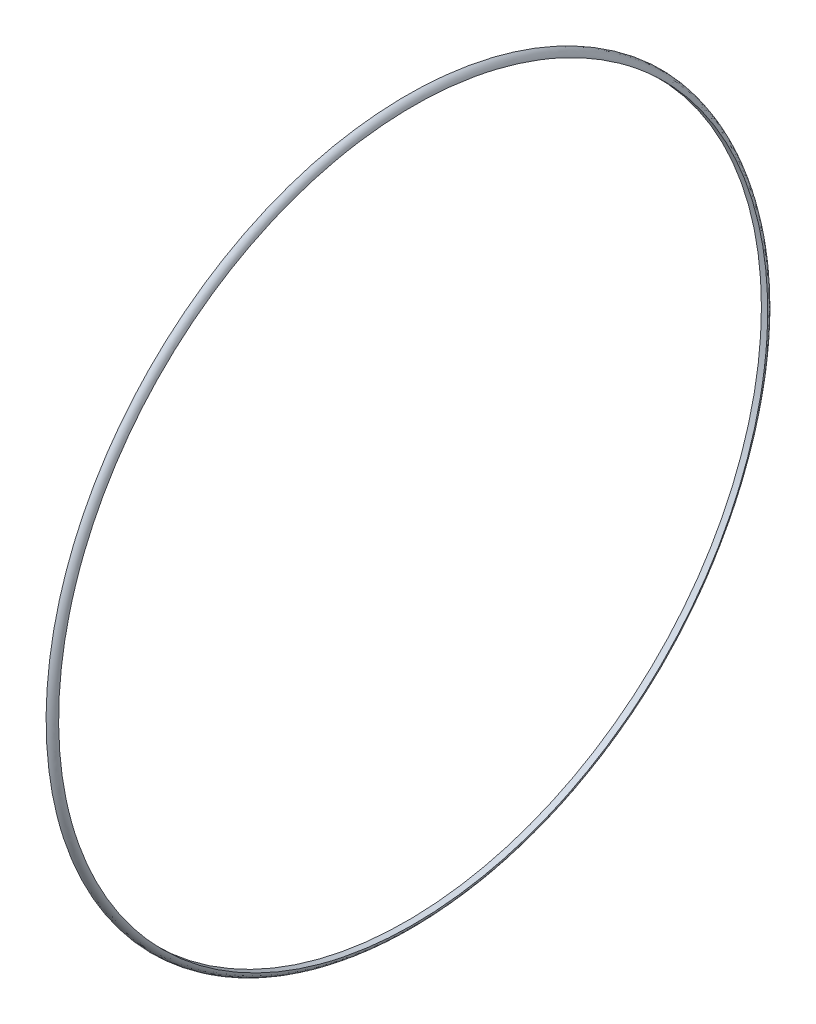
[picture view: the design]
ISO-10303-21;
HEADER;
FILE_DESCRIPTION(('STEP AP214'),'2;1');
FILE_NAME('part.step','',(''),(''),'','','');
FILE_SCHEMA(('AUTOMOTIVE_DESIGN { 1 0 10303 214 1 1 1 1 }'));
ENDSEC;
DATA;
#1=APPLICATION_CONTEXT('core data for automotive mechanical design processes');
#2=APPLICATION_PROTOCOL_DEFINITION('international standard','automotive_design',2000,#1);
#3=PRODUCT_CONTEXT('',#1,'mechanical');
#4=PRODUCT('Part','Part','',(#3));
#5=PRODUCT_RELATED_PRODUCT_CATEGORY('part','',(#4));
#6=PRODUCT_DEFINITION_FORMATION('','',#4);
#7=PRODUCT_DEFINITION_CONTEXT('part definition',#1,'design');
#8=PRODUCT_DEFINITION('design','',#6,#7);
#9=PRODUCT_DEFINITION_SHAPE('','',#8);
#10=(LENGTH_UNIT() NAMED_UNIT(*) SI_UNIT(.MILLI.,.METRE.));
#11=(NAMED_UNIT(*) PLANE_ANGLE_UNIT() SI_UNIT($,.RADIAN.));
#12=(NAMED_UNIT(*) SI_UNIT($,.STERADIAN.) SOLID_ANGLE_UNIT());
#13=UNCERTAINTY_MEASURE_WITH_UNIT(LENGTH_MEASURE(1.E-05),#10,'distance_accuracy_value','');
#14=(GEOMETRIC_REPRESENTATION_CONTEXT(3) GLOBAL_UNCERTAINTY_ASSIGNED_CONTEXT((#13)) GLOBAL_UNIT_ASSIGNED_CONTEXT((#10,
#11,#12)) REPRESENTATION_CONTEXT('',''));
#15=CARTESIAN_POINT('',(0.,0.,0.));
#16=DIRECTION('',(0.,0.,1.));
#17=DIRECTION('',(1.,0.,0.));
#18=AXIS2_PLACEMENT_3D('',#15,#16,#17);
#19=CARTESIAN_POINT('',(860.942596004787,1.34057465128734E-12,574.769949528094));
#20=DIRECTION('',(-1.,0.,0.));
#21=DIRECTION('',(0.,0.,1.));
#22=AXIS2_PLACEMENT_3D('',#19,#20,#21);
#23=CYLINDRICAL_SURFACE('',#22,15.113);
#24=CARTESIAN_POINT('',(857.907296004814,-5.03581855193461E-09,559.656949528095));
#25=CARTESIAN_POINT('',(857.907295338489,-0.199487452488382,559.656946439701));
#26=CARTESIAN_POINT('',(857.907260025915,-0.398936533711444,559.660896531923));
#27=CARTESIAN_POINT('',(857.90706303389,-0.998143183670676,559.684642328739));
#28=CARTESIAN_POINT('',(857.906809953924,-1.39751407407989,559.71638294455));
#29=CARTESIAN_POINT('',(857.906111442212,-2.19292731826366,559.811521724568));
#30=CARTESIAN_POINT('',(857.905665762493,-2.5889647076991,559.874960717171));
#31=CARTESIAN_POINT('',(857.904690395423,-3.37962317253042,560.034091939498));
#32=CARTESIAN_POINT('',(857.904159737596,-3.77416620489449,560.13017322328));
#33=CARTESIAN_POINT('',(857.90321322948,-4.55440358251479,560.353814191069));
#34=CARTESIAN_POINT('',(857.902797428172,-4.9400940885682,560.481387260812));
#35=CARTESIAN_POINT('',(857.902256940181,-5.69995149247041,560.767161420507));
#36=CARTESIAN_POINT('',(857.902132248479,-6.07411858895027,560.925361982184));
#37=CARTESIAN_POINT('',(857.902231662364,-6.80835340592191,561.271293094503));
#38=CARTESIAN_POINT('',(857.902455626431,-7.16842678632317,561.459011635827));
#39=CARTESIAN_POINT('',(857.903167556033,-7.88381970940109,561.869418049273));
#40=CARTESIAN_POINT('',(857.90366391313,-8.23859898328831,562.093048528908));
#41=CARTESIAN_POINT('',(857.904705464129,-8.92798209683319,562.568756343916));
#42=CARTESIAN_POINT('',(857.905250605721,-9.26260691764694,562.820803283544));
#43=CARTESIAN_POINT('',(857.906188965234,-9.9098059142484,563.351818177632));
#44=CARTESIAN_POINT('',(857.906582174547,-10.222378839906,563.630787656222));
#45=CARTESIAN_POINT('',(857.907093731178,-10.8235686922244,564.213969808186));
#46=CARTESIAN_POINT('',(857.90721181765,-11.1121626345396,564.5182061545));
#47=CARTESIAN_POINT('',(857.907296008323,-11.6667378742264,565.153809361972));
#48=CARTESIAN_POINT('',(857.907260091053,-11.9323714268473,565.485480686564));
#49=CARTESIAN_POINT('',(857.907205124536,-12.3091514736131,565.998821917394));
#50=CARTESIAN_POINT('',(857.90718661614,-12.4311591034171,566.172617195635));
#51=CARTESIAN_POINT('',(857.907172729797,-12.6677771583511,566.525237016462));
#52=CARTESIAN_POINT('',(857.907177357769,-12.7823856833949,566.704062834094));
#53=CARTESIAN_POINT('',(857.907218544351,-13.1149696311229,567.247916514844));
#54=CARTESIAN_POINT('',(857.907282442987,-13.3214956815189,567.62003752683));
#55=CARTESIAN_POINT('',(857.907433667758,-13.7024159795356,568.380316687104));
#56=CARTESIAN_POINT('',(857.907520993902,-13.8768102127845,568.768474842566));
#57=CARTESIAN_POINT('',(857.907648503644,-14.1921828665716,569.557918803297));
#58=CARTESIAN_POINT('',(857.907688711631,-14.3331785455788,569.959197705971));
#59=CARTESIAN_POINT('',(857.907686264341,-14.5808600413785,570.772214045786));
#60=CARTESIAN_POINT('',(857.907643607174,-14.6875450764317,571.183951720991));
#61=CARTESIAN_POINT('',(857.907510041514,-14.8658172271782,572.01482341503));
#62=CARTESIAN_POINT('',(857.907419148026,-14.9374152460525,572.433955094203));
#63=CARTESIAN_POINT('',(857.907312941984,-15.0450530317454,573.276757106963));
#64=CARTESIAN_POINT('',(857.907297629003,-15.0810929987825,573.700427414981));
#65=CARTESIAN_POINT('',(857.907284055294,-15.1173616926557,574.549351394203));
#66=CARTESIAN_POINT('',(857.907285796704,-15.1175859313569,574.974605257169));
#67=CARTESIAN_POINT('',(857.907303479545,-15.0822102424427,575.823620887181));
#68=CARTESIAN_POINT('',(857.907319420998,-15.0466102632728,576.247382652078));
#69=CARTESIAN_POINT('',(857.907423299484,-14.9398362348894,577.090424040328));
#70=CARTESIAN_POINT('',(857.907511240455,-14.868660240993,577.509703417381));
#71=CARTESIAN_POINT('',(857.907634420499,-14.6912392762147,578.340775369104));
#72=CARTESIAN_POINT('',(857.907669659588,-14.5849943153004,578.752567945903));
#73=CARTESIAN_POINT('',(857.907665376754,-14.3381937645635,579.565728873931));
#74=CARTESIAN_POINT('',(857.907625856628,-14.1976389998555,579.96709747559));
#75=CARTESIAN_POINT('',(857.90752646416,-13.8832167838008,580.756567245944));
#76=CARTESIAN_POINT('',(857.907466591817,-13.7093493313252,581.144668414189));
#77=CARTESIAN_POINT('',(857.907356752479,-13.3295390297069,581.904841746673));
#78=CARTESIAN_POINT('',(857.907306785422,-13.1235963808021,582.276914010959));
#79=CARTESIAN_POINT('',(857.907208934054,-12.6810990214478,583.002386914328));
#80=CARTESIAN_POINT('',(857.907161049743,-12.4445443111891,583.355787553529));
#81=CARTESIAN_POINT('',(857.907071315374,-11.9425036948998,584.041405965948));
#82=CARTESIAN_POINT('',(857.907029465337,-11.6770176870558,584.373623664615));
#83=CARTESIAN_POINT('',(857.906974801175,-11.119002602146,585.014512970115));
#84=CARTESIAN_POINT('',(857.906961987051,-10.8264735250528,585.323184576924));
#85=CARTESIAN_POINT('',(857.906974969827,-10.2164522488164,585.914786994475));
#86=CARTESIAN_POINT('',(857.907000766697,-9.89896006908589,586.197717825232));
#87=CARTESIAN_POINT('',(857.907073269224,-9.24126956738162,586.735827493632));
#88=CARTESIAN_POINT('',(857.907119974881,-8.90107124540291,586.991006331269));
#89=CARTESIAN_POINT('',(857.907213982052,-8.20038709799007,587.471797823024));
#90=CARTESIAN_POINT('',(857.907261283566,-7.83990127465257,587.697410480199));
#91=CARTESIAN_POINT('',(857.907361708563,-7.10120492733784,588.117465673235));
#92=CARTESIAN_POINT('',(857.907414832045,-6.72299440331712,588.311908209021));
#93=CARTESIAN_POINT('',(857.907528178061,-5.95153722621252,588.668240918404));
#94=CARTESIAN_POINT('',(857.907588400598,-5.55829056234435,588.830131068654));
#95=CARTESIAN_POINT('',(857.907664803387,-4.75955710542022,589.120207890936));
#96=CARTESIAN_POINT('',(857.90768098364,-4.35407031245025,589.248394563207));
#97=CARTESIAN_POINT('',(857.907631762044,-3.53373952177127,589.470153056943));
#98=CARTESIAN_POINT('',(857.907566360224,-3.11889552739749,589.563724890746));
#99=CARTESIAN_POINT('',(857.907428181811,-2.28279947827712,589.71558853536));
#100=CARTESIAN_POINT('',(857.907355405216,-1.86154742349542,589.773880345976));
#101=CARTESIAN_POINT('',(857.907289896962,-1.01563007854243,589.854769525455));
#102=CARTESIAN_POINT('',(857.907297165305,-0.590964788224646,589.877366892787));
#103=CARTESIAN_POINT('',(857.907293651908,0.258759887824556,589.886706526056));
#104=CARTESIAN_POINT('',(857.907282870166,0.683819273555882,589.873448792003));
#105=CARTESIAN_POINT('',(857.90732328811,1.53131043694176,589.811172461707));
#106=CARTESIAN_POINT('',(857.907374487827,1.95374221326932,589.762153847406));
#107=CARTESIAN_POINT('',(857.907507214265,2.79297469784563,589.62870423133));
#108=CARTESIAN_POINT('',(857.907588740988,3.20977540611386,589.544273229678));
#109=CARTESIAN_POINT('',(857.907674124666,4.03478220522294,589.34059917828));
#110=CARTESIAN_POINT('',(857.907677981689,4.44298830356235,589.221356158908));
#111=CARTESIAN_POINT('',(857.907626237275,5.24790414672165,588.94890579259));
#112=CARTESIAN_POINT('',(857.907570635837,5.6446138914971,588.795698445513));
#113=CARTESIAN_POINT('',(857.90745919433,6.42371654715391,588.456408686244));
#114=CARTESIAN_POINT('',(857.907403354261,6.80610946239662,588.270326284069));
#115=CARTESIAN_POINT('',(857.907299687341,7.55386000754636,587.866609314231));
#116=CARTESIAN_POINT('',(857.90725186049,7.91921763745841,587.648974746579));
#117=CARTESIAN_POINT('',(857.90715600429,8.63030055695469,587.183700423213));
#118=CARTESIAN_POINT('',(857.907107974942,8.97602582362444,586.936060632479));
#119=CARTESIAN_POINT('',(857.907026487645,9.64538565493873,586.412536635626));
#120=CARTESIAN_POINT('',(857.906993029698,9.9690202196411,586.136652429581));
#121=CARTESIAN_POINT('',(857.906961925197,10.5918968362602,585.55860186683));
#122=CARTESIAN_POINT('',(857.906964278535,10.8911389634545,585.256435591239));
#123=CARTESIAN_POINT('',(857.907003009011,11.46310439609,584.627968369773));
#124=CARTESIAN_POINT('',(857.90703938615,11.7358277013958,584.301667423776));
#125=CARTESIAN_POINT('',(857.907123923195,12.2528180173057,583.627248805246));
#126=CARTESIAN_POINT('',(857.907172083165,12.4970848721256,583.279131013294));
#127=CARTESIAN_POINT('',(857.907268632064,12.9554239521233,582.563555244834));
#128=CARTESIAN_POINT('',(857.907317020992,13.169496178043,582.196097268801));
#129=CARTESIAN_POINT('',(857.907422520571,13.5659289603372,581.444444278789));
#130=CARTESIAN_POINT('',(857.907479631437,13.7482887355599,581.060248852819));
#131=CARTESIAN_POINT('',(857.90758848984,14.0799936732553,580.277860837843));
#132=CARTESIAN_POINT('',(857.907640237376,14.2293388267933,579.879668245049));
#133=CARTESIAN_POINT('',(857.907678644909,14.4939454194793,579.072139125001));
#134=CARTESIAN_POINT('',(857.907665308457,14.6092087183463,578.662803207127));
#135=CARTESIAN_POINT('',(857.907566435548,14.804843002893,577.8358771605));
#136=CARTESIAN_POINT('',(857.907480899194,14.8852140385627,577.418287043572));
#137=CARTESIAN_POINT('',(857.907355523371,15.0104844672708,576.577875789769));
#138=CARTESIAN_POINT('',(857.907315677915,15.0553885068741,576.155055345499));
#139=CARTESIAN_POINT('',(857.907283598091,15.1094234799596,575.307132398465));
#140=CARTESIAN_POINT('',(857.907291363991,15.1185542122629,574.882029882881));
#141=CARTESIAN_POINT('',(857.907295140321,15.1009742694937,574.032429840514));
#142=CARTESIAN_POINT('',(857.907291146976,15.0742520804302,573.60793255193));
#143=CARTESIAN_POINT('',(857.907367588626,14.9851371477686,572.762708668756));
#144=CARTESIAN_POINT('',(857.9074480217,14.9227452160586,572.341981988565));
#145=CARTESIAN_POINT('',(857.907592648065,14.7626931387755,571.507062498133));
#146=CARTESIAN_POINT('',(857.907656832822,14.6650145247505,571.092873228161));
#147=CARTESIAN_POINT('',(857.907700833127,14.435078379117,570.274164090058));
#148=CARTESIAN_POINT('',(857.907680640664,14.3028175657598,569.869645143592));
#149=CARTESIAN_POINT('',(857.907579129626,14.0048564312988,569.073713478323));
#150=CARTESIAN_POINT('',(857.907497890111,13.8391995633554,568.682284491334));
#151=CARTESIAN_POINT('',(857.907339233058,13.4755838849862,567.914906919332));
#152=CARTESIAN_POINT('',(857.907261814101,13.2776371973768,567.538952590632));
#153=CARTESIAN_POINT('',(857.907178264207,12.8536026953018,566.809850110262));
#154=CARTESIAN_POINT('',(857.907171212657,12.6279175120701,566.456467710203));
#155=CARTESIAN_POINT('',(857.907218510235,12.1481313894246,565.769896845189));
#156=CARTESIAN_POINT('',(857.907272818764,11.8940493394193,565.436695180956));
#157=CARTESIAN_POINT('',(857.907272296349,11.3590141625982,564.792426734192));
#158=CARTESIAN_POINT('',(857.907217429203,11.0780521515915,564.481367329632));
#159=CARTESIAN_POINT('',(857.90684582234,10.4912792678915,563.883664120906));
#160=CARTESIAN_POINT('',(857.90652909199,10.1854692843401,563.59701944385));
#161=CARTESIAN_POINT('',(857.9056935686,9.55122821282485,563.050220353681));
#162=CARTESIAN_POINT('',(857.905174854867,9.22280604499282,562.790055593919));
#163=CARTESIAN_POINT('',(857.90412068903,8.54522398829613,562.29768231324));
#164=CARTESIAN_POINT('',(857.903585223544,8.19604730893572,562.065496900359));
#165=CARTESIAN_POINT('',(857.90272028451,7.47474568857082,561.627983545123));
#166=CARTESIAN_POINT('',(857.902393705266,7.10237361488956,561.423062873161));
#167=CARTESIAN_POINT('',(857.902112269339,6.34153252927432,561.045218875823));
#168=CARTESIAN_POINT('',(857.902157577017,5.95305647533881,560.87230973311));
#169=CARTESIAN_POINT('',(857.902594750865,5.16269935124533,560.559742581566));
#170=CARTESIAN_POINT('',(857.902986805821,4.76081109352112,560.420102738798));
#171=CARTESIAN_POINT('',(857.903934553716,3.94687333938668,560.175240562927));
#172=CARTESIAN_POINT('',(857.904490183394,3.53482782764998,560.070004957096));
#173=CARTESIAN_POINT('',(857.905651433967,2.606325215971,559.874166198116));
#174=CARTESIAN_POINT('',(857.906238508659,2.08792215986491,559.792694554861));
#175=CARTESIAN_POINT('',(857.907061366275,1.04625156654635,559.684136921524));
#176=CARTESIAN_POINT('',(857.907297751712,0.522993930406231,559.656957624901));
#177=CARTESIAN_POINT('',(857.907296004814,-5.03581855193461E-09,559.656949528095));
#178=B_SPLINE_CURVE_WITH_KNOTS('',3,(#24,#25,#26,#27,#28,#29,#30,#31,#32,#33,#34,#35,#36,#37,
#38,#39,#40,#41,#42,#43,#44,#45,#46,#47,#48,#49,#50,#51,#52,#53,#54,#55,#56,#57,#58,#59,#60,#61,
#62,#63,#64,#65,#66,#67,#68,#69,#70,#71,#72,#73,#74,#75,#76,#77,#78,#79,#80,#81,#82,#83,#84,#85,
#86,#87,#88,#89,#90,#91,#92,#93,#94,#95,#96,#97,#98,#99,#100,#101,#102,#103,#104,#105,#106,#107,
#108,#109,#110,#111,#112,#113,#114,#115,#116,#117,#118,#119,#120,#121,#122,#123,#124,#125,#126,
#127,#128,#129,#130,#131,#132,#133,#134,#135,#136,#137,#138,#139,#140,#141,#142,#143,#144,#145,
#146,#147,#148,#149,#150,#151,#152,#153,#154,#155,#156,#157,#158,#159,#160,#161,#162,#163,#164,
#165,#166,#167,#168,#169,#170,#171,#172,#173,#174,#175,#176,#177),.UNSPECIFIED.,.T.,.F.,(4,2,2,
2,2,2,2,2,2,2,2,2,2,2,2,2,2,2,2,2,2,2,2,2,2,2,2,2,2,2,2,2,2,2,2,2,2,2,2,2,2,2,2,2,2,2,2,2,2,2,2,
2,2,2,2,2,2,2,2,2,2,2,2,2,2,2,2,2,2,2,2,2,2,2,2,2,4),(0.,0.598375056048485,1.79885640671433,
3.00088801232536,4.2177804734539,5.43519107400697,6.65258067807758,7.86947626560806,
9.12615554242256,10.3815031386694,11.6369218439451,12.8935303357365,14.1666833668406,
14.8035578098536,15.440595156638,16.7157198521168,17.9908451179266,19.2653100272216,
20.5398039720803,21.8139016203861,23.0879920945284,24.3622422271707,25.6364941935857,
26.910815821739,28.1851370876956,29.4594277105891,30.7337183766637,32.0080010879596,
33.2822837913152,34.5565709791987,35.8308581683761,37.1051443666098,38.3794305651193,
39.6537166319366,40.9280027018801,42.2022896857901,43.4765766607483,44.7508631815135,
46.0251497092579,47.299436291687,48.5737228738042,49.8480100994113,51.1222973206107,
52.396583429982,53.6708695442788,54.9451552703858,56.2194409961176,57.4937282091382,
58.7680154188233,60.0422986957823,61.3165819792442,62.5908722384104,63.865162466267,
65.139484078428,66.4138060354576,67.688058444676,68.9623090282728,70.2363926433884,
71.5104834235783,72.7849834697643,74.0594545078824,75.3345935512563,76.6098536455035,
77.8834650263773,79.156599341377,80.4130551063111,81.6686800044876,82.9247213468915,
84.1807177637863,85.4362215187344,86.6927551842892,87.9663422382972,89.2404922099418,
90.5153363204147,91.7896880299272,93.3611440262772,94.9298969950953),.UNSPECIFIED.);
#179=CARTESIAN_POINT('',(857.907296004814,-5.03581594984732E-09,559.656949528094));
#180=VERTEX_POINT('',#179);
#181=EDGE_CURVE('E58',#180,#180,#178,.T.);
#182=ORIENTED_EDGE('',*,*,#181,.F.);
#183=EDGE_LOOP('',(#182));
#184=FACE_BOUND('',#183,.T.);
#185=CARTESIAN_POINT('',(857.640596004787,1.34094124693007E-12,574.769949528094));
#186=DIRECTION('',(1.,0.,0.));
#187=DIRECTION('',(0.,0.,-1.));
#188=AXIS2_PLACEMENT_3D('',#185,#186,#187);
#189=CIRCLE('',#188,15.113);
#190=CARTESIAN_POINT('',(857.640596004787,1.34261912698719E-12,559.656949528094));
#191=VERTEX_POINT('',#190);
#192=EDGE_CURVE('E68',#191,#191,#189,.T.);
#193=ORIENTED_EDGE('',*,*,#192,.F.);
#194=EDGE_LOOP('',(#193));
#195=FACE_BOUND('',#194,.T.);
#196=ADVANCED_FACE('F54',(#184,#195),#23,.F.);
#197=CARTESIAN_POINT('',(857.640596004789,-44.721359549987,1039.76994952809));
#198=DIRECTION('',(1.,0.,0.));
#199=DIRECTION('',(0.,0.,-1.));
#200=AXIS2_PLACEMENT_3D('',#197,#198,#199);
#201=PLANE('',#200);
#202=CARTESIAN_POINT('',(857.640596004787,-2.28525228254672E-09,559.390249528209));
#203=CARTESIAN_POINT('',(857.640596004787,0.099759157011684,559.39024904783));
#204=CARTESIAN_POINT('',(857.640596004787,0.1995083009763,559.39130400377));
#205=CARTESIAN_POINT('',(857.640596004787,0.398935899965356,559.395500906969));
#206=CARTESIAN_POINT('',(857.640596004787,0.498614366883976,559.398642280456));
#207=CARTESIAN_POINT('',(857.640596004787,0.998278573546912,559.419581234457));
#208=CARTESIAN_POINT('',(857.640596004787,1.39773441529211,559.453013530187));
#209=CARTESIAN_POINT('',(857.640596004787,2.19284643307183,559.551839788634));
#210=CARTESIAN_POINT('',(857.640596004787,2.58849966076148,559.617256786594));
#211=CARTESIAN_POINT('',(857.640596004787,3.37326136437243,559.778644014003));
#212=CARTESIAN_POINT('',(857.640596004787,3.76237431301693,559.874592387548));
#213=CARTESIAN_POINT('',(857.640596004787,4.53198115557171,560.095693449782));
#214=CARTESIAN_POINT('',(857.640596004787,4.91247675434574,560.220840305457));
#215=CARTESIAN_POINT('',(857.640596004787,6.03834133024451,560.638501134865));
#216=CARTESIAN_POINT('',(857.640596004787,6.76870396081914,560.973364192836));
#217=CARTESIAN_POINT('',(857.640596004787,7.81997513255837,561.553874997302));
#218=CARTESIAN_POINT('',(857.640596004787,8.16316751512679,561.760527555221));
#219=CARTESIAN_POINT('',(857.640596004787,8.83289222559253,562.199316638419));
#220=CARTESIAN_POINT('',(857.640596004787,9.15942838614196,562.43144726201));
#221=CARTESIAN_POINT('',(857.640596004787,9.79349629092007,562.920533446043));
#222=CARTESIAN_POINT('',(857.640596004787,10.1010246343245,563.177493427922));
#223=CARTESIAN_POINT('',(857.640596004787,10.5460580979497,563.580969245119));
#224=CARTESIAN_POINT('',(857.640596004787,10.691752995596,563.718531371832));
#225=CARTESIAN_POINT('',(857.640596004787,10.9773461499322,563.999579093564));
#226=CARTESIAN_POINT('',(857.640596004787,11.1172437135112,564.143065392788));
#227=CARTESIAN_POINT('',(857.640596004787,11.5311439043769,564.585422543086));
#228=CARTESIAN_POINT('',(857.640596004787,11.7958864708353,564.893050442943));
#229=CARTESIAN_POINT('',(857.640596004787,12.2998090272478,565.528739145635));
#230=CARTESIAN_POINT('',(857.640596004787,12.5389747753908,565.85681117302));
#231=CARTESIAN_POINT('',(857.640596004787,12.9913641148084,566.530597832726));
#232=CARTESIAN_POINT('',(857.640596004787,13.2045756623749,566.876320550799));
#233=CARTESIAN_POINT('',(857.640596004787,13.6033081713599,567.583173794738));
#234=CARTESIAN_POINT('',(857.640596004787,13.7888423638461,567.944296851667));
#235=CARTESIAN_POINT('',(857.640596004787,14.1391580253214,568.698115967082));
#236=CARTESIAN_POINT('',(857.640596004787,14.3024783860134,569.09149216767));
#237=CARTESIAN_POINT('',(857.640596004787,14.5951885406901,569.890219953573));
#238=CARTESIAN_POINT('',(857.640596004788,14.724617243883,570.295557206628));
#239=CARTESIAN_POINT('',(857.640596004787,14.8927399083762,570.910637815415));
#240=CARTESIAN_POINT('',(857.640596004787,14.9444547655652,571.116901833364));
#241=CARTESIAN_POINT('',(857.640596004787,15.0391528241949,571.531417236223));
#242=CARTESIAN_POINT('',(857.640596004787,15.0821361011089,571.739668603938));
#243=CARTESIAN_POINT('',(857.640596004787,15.1981086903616,572.367009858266));
#244=CARTESIAN_POINT('',(857.640596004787,15.2580979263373,572.788602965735));
#245=CARTESIAN_POINT('',(857.640596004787,15.3222141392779,573.42339273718));
#246=CARTESIAN_POINT('',(857.640596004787,15.339275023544,573.635393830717));
#247=CARTESIAN_POINT('',(857.640596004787,15.3647109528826,574.059932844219));
#248=CARTESIAN_POINT('',(857.640596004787,15.3730861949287,574.272470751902));
#249=CARTESIAN_POINT('',(857.640596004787,15.3809902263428,574.697640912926));
#250=CARTESIAN_POINT('',(857.640596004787,15.3805217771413,574.910273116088));
#251=CARTESIAN_POINT('',(857.640596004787,15.3707627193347,575.335338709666));
#252=CARTESIAN_POINT('',(857.640596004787,15.3614719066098,575.547772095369));
#253=CARTESIAN_POINT('',(857.640596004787,15.3342183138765,575.97201770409));
#254=CARTESIAN_POINT('',(857.640596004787,15.3162582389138,576.183830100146));
#255=CARTESIAN_POINT('',(857.640596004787,15.2717223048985,576.606524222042));
#256=CARTESIAN_POINT('',(857.640596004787,15.2451467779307,576.817405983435));
#257=CARTESIAN_POINT('',(857.640596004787,15.1524137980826,577.448531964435));
#258=CARTESIAN_POINT('',(857.640596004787,15.0732692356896,577.866955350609));
#259=CARTESIAN_POINT('',(857.640596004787,14.879755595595,578.696500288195));
#260=CARTESIAN_POINT('',(857.640596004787,14.765310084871,579.107603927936));
#261=CARTESIAN_POINT('',(857.640596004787,14.5020222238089,579.918866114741));
#262=CARTESIAN_POINT('',(857.640596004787,14.3531632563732,580.319019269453));
#263=CARTESIAN_POINT('',(857.640596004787,14.0226374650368,581.105553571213));
#264=CARTESIAN_POINT('',(857.640596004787,13.840968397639,581.491933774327));
#265=CARTESIAN_POINT('',(857.640596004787,13.4463008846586,582.248137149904));
#266=CARTESIAN_POINT('',(857.640596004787,13.2333160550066,582.617967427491));
#267=CARTESIAN_POINT('',(857.640596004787,12.7788441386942,583.336353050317));
#268=CARTESIAN_POINT('',(857.640596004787,12.5375489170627,583.685029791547));
#269=CARTESIAN_POINT('',(857.640596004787,12.0273237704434,584.361000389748));
#270=CARTESIAN_POINT('',(857.640596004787,11.7584211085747,584.688314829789));
#271=CARTESIAN_POINT('',(857.640596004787,11.194604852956,585.319977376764));
#272=CARTESIAN_POINT('',(857.640596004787,10.8996796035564,585.624315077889));
#273=CARTESIAN_POINT('',(857.640596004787,10.2859338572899,586.207847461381));
#274=CARTESIAN_POINT('',(857.640596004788,9.96711380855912,586.487042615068));
#275=CARTESIAN_POINT('',(857.640596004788,9.30755771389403,587.018362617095));
#276=CARTESIAN_POINT('',(857.640596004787,8.96681775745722,587.270482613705));
#277=CARTESIAN_POINT('',(857.640596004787,8.2658010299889,587.745698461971));
#278=CARTESIAN_POINT('',(857.640596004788,7.90552896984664,587.968801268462));
#279=CARTESIAN_POINT('',(857.640596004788,7.16790088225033,588.384547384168));
#280=CARTESIAN_POINT('',(857.640596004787,6.79054987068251,588.577199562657));
#281=CARTESIAN_POINT('',(857.640596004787,6.21352100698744,588.842399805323));
#282=CARTESIAN_POINT('',(857.640596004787,6.01924497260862,588.926872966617));
#283=CARTESIAN_POINT('',(857.640596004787,5.62733748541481,589.087713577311));
#284=CARTESIAN_POINT('',(857.640596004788,5.42970553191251,589.164079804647));
#285=CARTESIAN_POINT('',(857.640596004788,4.83022811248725,589.381396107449));
#286=CARTESIAN_POINT('',(857.640596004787,4.42367805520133,589.509699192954));
#287=CARTESIAN_POINT('',(857.640596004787,3.8068803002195,589.676030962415));
#288=CARTESIAN_POINT('',(857.640596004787,3.60004324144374,589.727134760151));
#289=CARTESIAN_POINT('',(857.640596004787,3.18438566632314,589.820571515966));
#290=CARTESIAN_POINT('',(857.640596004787,2.97556520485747,589.862904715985));
#291=CARTESIAN_POINT('',(857.640596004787,2.55632176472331,589.938848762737));
#292=CARTESIAN_POINT('',(857.640596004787,2.34589860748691,589.972458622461));
#293=CARTESIAN_POINT('',(857.640596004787,1.92386237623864,590.031017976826));
#294=CARTESIAN_POINT('',(857.640596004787,1.71224925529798,590.055967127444));
#295=CARTESIAN_POINT('',(857.640596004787,1.07632427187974,590.117816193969));
#296=CARTESIAN_POINT('',(857.640596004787,0.650640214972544,590.14176940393));
#297=CARTESIAN_POINT('',(857.640596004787,0.0121519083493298,590.151107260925));
#298=CARTESIAN_POINT('',(857.640596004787,-0.200561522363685,590.149795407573));
#299=CARTESIAN_POINT('',(857.640596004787,-0.625733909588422,590.138360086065));
#300=CARTESIAN_POINT('',(857.640596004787,-0.83819290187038,590.128238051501));
#301=CARTESIAN_POINT('',(857.640596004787,-1.26231950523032,590.099337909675));
#302=CARTESIAN_POINT('',(857.640596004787,-1.47398766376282,590.080567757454));
#303=CARTESIAN_POINT('',(857.640596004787,-1.89639373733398,590.034413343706));
#304=CARTESIAN_POINT('',(857.640596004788,-2.10713160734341,590.007028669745));
#305=CARTESIAN_POINT('',(857.640596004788,-2.52555002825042,589.94390545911));
#306=CARTESIAN_POINT('',(857.640596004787,-2.73324139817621,589.908238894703));
#307=CARTESIAN_POINT('',(857.640596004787,-3.14695366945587,589.828346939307));
#308=CARTESIAN_POINT('',(857.640596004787,-3.35297461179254,589.784121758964));
#309=CARTESIAN_POINT('',(857.640596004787,-3.96805266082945,589.638564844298));
#310=CARTESIAN_POINT('',(857.640596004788,-4.3741443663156,589.524348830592));
#311=CARTESIAN_POINT('',(857.640596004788,-5.17525217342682,589.262424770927));
#312=CARTESIAN_POINT('',(857.640596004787,-5.57026965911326,589.11472093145));
#313=CARTESIAN_POINT('',(857.640596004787,-6.34685258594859,588.787320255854));
#314=CARTESIAN_POINT('',(857.640596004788,-6.7284170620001,588.607621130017));
#315=CARTESIAN_POINT('',(857.640596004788,-7.47554746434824,588.217565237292));
#316=CARTESIAN_POINT('',(857.640596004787,-7.84111305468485,588.007207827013));
#317=CARTESIAN_POINT('',(857.640596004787,-8.55366118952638,587.557266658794));
#318=CARTESIAN_POINT('',(857.640596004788,-8.90064854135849,587.317690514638));
#319=CARTESIAN_POINT('',(857.640596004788,-9.57370776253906,586.811033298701));
#320=CARTESIAN_POINT('',(857.640596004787,-9.89978773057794,586.543962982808));
#321=CARTESIAN_POINT('',(857.640596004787,-10.529413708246,585.98388576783));
#322=CARTESIAN_POINT('',(857.640596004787,-10.8329376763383,585.690854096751));
#323=CARTESIAN_POINT('',(857.640596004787,-11.4190233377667,585.076967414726));
#324=CARTESIAN_POINT('',(857.640596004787,-11.7012500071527,584.755792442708));
#325=CARTESIAN_POINT('',(857.640596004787,-12.2382478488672,584.091018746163));
#326=CARTESIAN_POINT('',(857.640596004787,-12.4930072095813,583.747410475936));
#327=CARTESIAN_POINT('',(857.640596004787,-12.9730377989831,583.040198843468));
#328=CARTESIAN_POINT('',(857.640596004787,-13.1983093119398,582.676595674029));
#329=CARTESIAN_POINT('',(857.640596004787,-13.6177878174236,581.932038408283));
#330=CARTESIAN_POINT('',(857.640596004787,-13.812008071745,581.551091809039));
#331=CARTESIAN_POINT('',(857.640596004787,-14.079160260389,580.968375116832));
#332=CARTESIAN_POINT('',(857.640596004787,-14.1642392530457,580.772092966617));
#333=CARTESIAN_POINT('',(857.640596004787,-14.3260980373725,580.376180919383));
#334=CARTESIAN_POINT('',(857.640596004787,-14.4028792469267,580.176551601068));
#335=CARTESIAN_POINT('',(857.640596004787,-14.620324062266,579.573406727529));
#336=CARTESIAN_POINT('',(857.640596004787,-14.7482911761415,579.165193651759));
#337=CARTESIAN_POINT('',(857.640596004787,-14.9136954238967,578.546769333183));
#338=CARTESIAN_POINT('',(857.640596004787,-14.9643409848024,578.339973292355));
#339=CARTESIAN_POINT('',(857.640596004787,-15.0568742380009,577.924414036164));
#340=CARTESIAN_POINT('',(857.640596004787,-15.0987620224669,577.715650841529));
#341=CARTESIAN_POINT('',(857.640596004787,-15.1738387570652,577.296507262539));
#342=CARTESIAN_POINT('',(857.640596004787,-15.2070250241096,577.086126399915));
#343=CARTESIAN_POINT('',(857.640596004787,-15.264751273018,576.664178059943));
#344=CARTESIAN_POINT('',(857.640596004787,-15.289291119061,576.452610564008));
#345=CARTESIAN_POINT('',(857.640596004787,-15.329702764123,576.028682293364));
#346=CARTESIAN_POINT('',(857.640596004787,-15.3455758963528,575.816321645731));
#347=CARTESIAN_POINT('',(857.640596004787,-15.3685992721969,575.391132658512));
#348=CARTESIAN_POINT('',(857.640596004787,-15.375749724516,575.178304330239));
#349=CARTESIAN_POINT('',(857.640596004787,-15.3811609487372,574.752578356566));
#350=CARTESIAN_POINT('',(857.640596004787,-15.3794237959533,574.539680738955));
#351=CARTESIAN_POINT('',(857.640596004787,-15.3671341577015,574.114155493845));
#352=CARTESIAN_POINT('',(857.640596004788,-15.3565814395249,573.901527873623));
#353=CARTESIAN_POINT('',(857.640596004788,-15.3119173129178,573.26467446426));
#354=CARTESIAN_POINT('',(857.640596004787,-15.264802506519,572.841255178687));
#355=CARTESIAN_POINT('',(857.640596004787,-15.168244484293,572.210075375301));
#356=CARTESIAN_POINT('',(857.640596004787,-15.13171965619,572.000237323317));
#357=CARTESIAN_POINT('',(857.640596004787,-15.0499326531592,571.582271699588));
#358=CARTESIAN_POINT('',(857.640596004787,-15.0046707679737,571.374144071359));
#359=CARTESIAN_POINT('',(857.640596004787,-14.8559495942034,570.753740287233));
#360=CARTESIAN_POINT('',(857.640596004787,-14.7394140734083,570.344518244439));
#361=CARTESIAN_POINT('',(857.640596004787,-14.4721244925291,569.537263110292));
#362=CARTESIAN_POINT('',(857.640596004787,-14.3213552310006,569.139235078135));
#363=CARTESIAN_POINT('',(857.640596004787,-13.9870915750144,568.357061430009));
#364=CARTESIAN_POINT('',(857.640596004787,-13.8035886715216,567.97291945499));
#365=CARTESIAN_POINT('',(857.640596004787,-13.4056861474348,567.221018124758));
#366=CARTESIAN_POINT('',(857.640596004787,-13.1912908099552,566.853256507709));
#367=CARTESIAN_POINT('',(857.640596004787,-12.848101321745,566.315881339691));
#368=CARTESIAN_POINT('',(857.640596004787,-12.7301830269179,566.139236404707));
#369=CARTESIAN_POINT('',(857.640596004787,-12.4872738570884,565.790931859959));
#370=CARTESIAN_POINT('',(857.640596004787,-12.362284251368,565.619271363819));
#371=CARTESIAN_POINT('',(857.640596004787,-11.9769779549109,565.112739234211));
#372=CARTESIAN_POINT('',(857.640596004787,-11.7060069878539,564.785819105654));
#373=CARTESIAN_POINT('',(857.640596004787,-11.2836513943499,564.318889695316));
#374=CARTESIAN_POINT('',(857.640596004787,-11.1426042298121,564.169381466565));
#375=CARTESIAN_POINT('',(857.640596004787,-10.8542804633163,563.876477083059));
#376=CARTESIAN_POINT('',(857.640596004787,-10.7070039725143,563.733080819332));
#377=CARTESIAN_POINT('',(857.640596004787,-10.4065156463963,563.452526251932));
#378=CARTESIAN_POINT('',(857.640596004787,-10.2533013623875,563.315370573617));
#379=CARTESIAN_POINT('',(857.640596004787,-9.94138884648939,563.047458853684));
#380=CARTESIAN_POINT('',(857.640596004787,-9.78269052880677,562.916702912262));
#381=CARTESIAN_POINT('',(857.640596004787,-9.29906773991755,562.534326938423));
#382=CARTESIAN_POINT('',(857.640596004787,-8.96639946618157,562.292397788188));
#383=CARTESIAN_POINT('',(857.640596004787,-8.28337782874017,561.835427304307));
#384=CARTESIAN_POINT('',(857.640596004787,-7.93303223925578,561.620374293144));
#385=CARTESIAN_POINT('',(857.640596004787,-7.21713621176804,561.217967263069));
#386=CARTESIAN_POINT('',(857.640596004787,-6.85159802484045,561.030591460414));
#387=CARTESIAN_POINT('',(857.640596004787,-6.10672129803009,560.684001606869));
#388=CARTESIAN_POINT('',(857.640596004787,-5.72736196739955,560.524832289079));
#389=CARTESIAN_POINT('',(857.640596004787,-4.91594004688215,560.22048228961));
#390=CARTESIAN_POINT('',(857.640596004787,-4.48260940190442,560.078667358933));
#391=CARTESIAN_POINT('',(857.640596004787,-3.6050095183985,559.832984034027));
#392=CARTESIAN_POINT('',(857.640596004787,-3.16073371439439,559.729139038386));
#393=CARTESIAN_POINT('',(857.640596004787,-2.26551596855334,559.561582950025));
#394=CARTESIAN_POINT('',(857.640596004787,-1.81458782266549,559.497798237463));
#395=CARTESIAN_POINT('',(857.640596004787,-0.909034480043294,559.41215312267));
#396=CARTESIAN_POINT('',(857.640596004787,-0.454413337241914,559.390251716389));
#397=CARTESIAN_POINT('',(857.640596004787,-2.28525228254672E-09,559.390249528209));
#398=B_SPLINE_CURVE_WITH_KNOTS('',3,(#202,#203,#204,#205,#206,#207,#208,#209,#210,#211,#212,
#213,#214,#215,#216,#217,#218,#219,#220,#221,#222,#223,#224,#225,#226,#227,#228,#229,#230,#231,
#232,#233,#234,#235,#236,#237,#238,#239,#240,#241,#242,#243,#244,#245,#246,#247,#248,#249,#250,
#251,#252,#253,#254,#255,#256,#257,#258,#259,#260,#261,#262,#263,#264,#265,#266,#267,#268,#269,
#270,#271,#272,#273,#274,#275,#276,#277,#278,#279,#280,#281,#282,#283,#284,#285,#286,#287,#288,
#289,#290,#291,#292,#293,#294,#295,#296,#297,#298,#299,#300,#301,#302,#303,#304,#305,#306,#307,
#308,#309,#310,#311,#312,#313,#314,#315,#316,#317,#318,#319,#320,#321,#322,#323,#324,#325,#326,
#327,#328,#329,#330,#331,#332,#333,#334,#335,#336,#337,#338,#339,#340,#341,#342,#343,#344,#345,
#346,#347,#348,#349,#350,#351,#352,#353,#354,#355,#356,#357,#358,#359,#360,#361,#362,#363,#364,
#365,#366,#367,#368,#369,#370,#371,#372,#373,#374,#375,#376,#377,#378,#379,#380,#381,#382,#383,
#384,#385,#386,#387,#388,#389,#390,#391,#392,#393,#394,#395,#396,#397),.UNSPECIFIED.,.T.,.F.,(4,
2,2,2,2,2,2,2,2,2,2,2,2,2,2,2,2,2,2,2,2,2,2,2,2,2,2,2,2,2,2,2,2,2,2,2,2,2,2,2,2,2,2,2,2,2,2,2,2,
2,2,2,2,2,2,2,2,2,2,2,2,2,2,2,2,2,2,2,2,2,2,2,2,2,2,2,2,2,2,2,2,2,2,2,2,2,2,2,2,2,2,2,2,2,2,2,2,
4),(0.,0.299252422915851,0.598422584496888,1.79944814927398,3.00133996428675,4.20237333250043,
5.40316697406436,7.80288449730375,9.00384706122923,10.2045320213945,11.4054311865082,
12.0064074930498,12.6074554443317,13.8235440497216,15.0403063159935,16.2576310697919,
17.47437200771,18.7506944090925,20.0255450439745,20.6633232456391,21.3010959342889,
22.5769014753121,23.2148310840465,23.8527462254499,24.490462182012,25.1281928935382,
25.7657247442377,26.4032320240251,27.6791503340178,28.957850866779,30.2371701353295,
31.5165769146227,32.795429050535,34.0660667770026,35.3354615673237,36.6054278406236,
37.8753703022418,39.1455399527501,40.4154046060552,41.6848987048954,42.3202780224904,
42.9557529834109,44.2328839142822,44.8719095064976,45.5109174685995,46.1499977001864,
46.7891033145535,48.0664433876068,48.7044555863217,49.3423639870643,49.9796867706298,
50.6170400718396,51.2490491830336,51.8810427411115,53.1449712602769,54.4087411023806,
55.6726014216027,56.9364882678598,58.200046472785,59.4631122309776,60.7273964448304,
62.0086059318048,63.2903641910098,64.5721100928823,65.8533070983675,66.4949259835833,
67.1364350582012,68.4180031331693,69.0565823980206,69.6951549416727,70.3339241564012,
70.9727034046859,71.6113843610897,72.2500500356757,72.8885665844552,73.527099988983,
74.8034998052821,75.4423329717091,76.0811449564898,77.3559710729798,78.6313643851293,
79.907089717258,81.1826383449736,81.8196447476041,82.4565371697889,83.7285568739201,
84.3450389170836,84.9615099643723,85.5782380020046,86.1949756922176,87.4275686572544,
88.6596241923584,89.8907047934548,91.1237206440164,92.4898621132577,93.8568440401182,
95.2213064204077,96.5844322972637),.UNSPECIFIED.);
#399=CARTESIAN_POINT('',(857.640596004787,-2.28525098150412E-09,559.390249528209));
#400=VERTEX_POINT('',#399);
#401=EDGE_CURVE('E11',#400,#400,#398,.T.);
#402=ORIENTED_EDGE('',*,*,#401,.F.);
#403=EDGE_LOOP('',(#402));
#404=FACE_BOUND('',#403,.T.);
#405=ORIENTED_EDGE('',*,*,#192,.T.);
#406=EDGE_LOOP('',(#405));
#407=FACE_BOUND('',#406,.T.);
#408=ADVANCED_FACE('F72',(#404,#407),#201,.F.);
#409=CARTESIAN_POINT('',(857.640596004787,-2.28525098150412E-09,559.390249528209));
#410=CARTESIAN_POINT('',(857.640596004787,-4.03269256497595,559.390249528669));
#411=CARTESIAN_POINT('',(857.640596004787,-9.07355826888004,561.544392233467));
#412=CARTESIAN_POINT('',(857.640596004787,-12.8254971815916,566.117077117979));
#413=CARTESIAN_POINT('',(857.640596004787,-14.2580200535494,568.74202856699));
#414=CARTESIAN_POINT('',(857.640596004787,-15.1641462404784,571.630059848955));
#415=CARTESIAN_POINT('',(857.640596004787,-15.487430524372,574.769949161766));
#416=CARTESIAN_POINT('',(857.640596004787,-15.1643316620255,577.909840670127));
#417=CARTESIAN_POINT('',(857.640596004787,-14.257278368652,580.797865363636));
#418=CARTESIAN_POINT('',(857.640596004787,-12.8282785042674,583.422840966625));
#419=CARTESIAN_POINT('',(857.640596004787,-10.9391441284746,585.709093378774));
#420=CARTESIAN_POINT('',(857.640596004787,-8.65289135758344,587.598229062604));
#421=CARTESIAN_POINT('',(857.640596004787,-6.02791588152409,589.027224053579));
#422=CARTESIAN_POINT('',(857.640596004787,-3.139891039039,589.934295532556));
#423=CARTESIAN_POINT('',(857.640596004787,-1.93967459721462E-10,590.257326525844));
#424=CARTESIAN_POINT('',(857.640596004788,3.13989103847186,589.934295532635));
#425=CARTESIAN_POINT('',(857.640596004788,6.02791588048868,589.027224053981));
#426=CARTESIAN_POINT('',(857.640596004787,8.65289135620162,587.5982290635));
#427=CARTESIAN_POINT('',(857.640596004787,10.9391441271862,585.709093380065));
#428=CARTESIAN_POINT('',(857.640596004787,12.8282785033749,583.422840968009));
#429=CARTESIAN_POINT('',(857.640596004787,14.2572783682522,580.797865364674));
#430=CARTESIAN_POINT('',(857.640596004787,15.1643316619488,577.909840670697));
#431=CARTESIAN_POINT('',(857.640596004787,15.4874305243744,574.769949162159));
#432=CARTESIAN_POINT('',(857.640596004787,15.1641462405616,571.630059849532));
#433=CARTESIAN_POINT('',(857.640596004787,14.2580200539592,568.742028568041));
#434=CARTESIAN_POINT('',(857.640596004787,12.8254971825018,566.11707711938));
#435=CARTESIAN_POINT('',(857.640596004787,9.07355827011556,561.544392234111));
#436=CARTESIAN_POINT('',(857.640596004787,4.03269256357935,559.39024952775));
#437=CARTESIAN_POINT('',(857.640596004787,-2.28525098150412E-09,559.390249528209));
#438=CARTESIAN_POINT('',(857.78736048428,-3.20210603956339E-09,559.405824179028));
#439=CARTESIAN_POINT('',(857.78736048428,-4.02853507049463,559.405824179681));
#440=CARTESIAN_POINT('',(857.78736048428,-9.06420390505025,561.557431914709));
#441=CARTESIAN_POINT('',(857.78736048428,-12.8126663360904,566.126103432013));
#442=CARTESIAN_POINT('',(857.78736048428,-14.2436927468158,568.748668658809));
#443=CARTESIAN_POINT('',(857.78736048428,-15.1488258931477,571.633844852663));
#444=CARTESIAN_POINT('',(857.78736048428,-15.4717289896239,574.769949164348));
#445=CARTESIAN_POINT('',(857.787360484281,-15.1490102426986,577.906055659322));
#446=CARTESIAN_POINT('',(857.787360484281,-14.2429553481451,580.791225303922));
#447=CARTESIAN_POINT('',(857.787360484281,-12.8154315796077,583.413814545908));
#448=CARTESIAN_POINT('',(857.787360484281,-10.9281115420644,585.69806079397));
#449=CARTESIAN_POINT('',(857.787360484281,-8.64386493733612,587.585382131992));
#450=CARTESIAN_POINT('',(857.787360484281,-6.02127582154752,589.012901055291));
#451=CARTESIAN_POINT('',(857.78736048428,-3.13610602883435,589.918974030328));
#452=CARTESIAN_POINT('',(857.78736048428,-1.64026585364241E-11,590.241625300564));
#453=CARTESIAN_POINT('',(857.78736048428,3.13610602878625,589.918974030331));
#454=CARTESIAN_POINT('',(857.787360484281,6.02127582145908,589.01290105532));
#455=CARTESIAN_POINT('',(857.78736048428,8.64386493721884,587.585382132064));
#456=CARTESIAN_POINT('',(857.78736048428,10.928111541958,585.698060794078));
#457=CARTESIAN_POINT('',(857.78736048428,12.8154315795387,583.413814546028));
#458=CARTESIAN_POINT('',(857.787360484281,14.2429553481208,580.791225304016));
#459=CARTESIAN_POINT('',(857.78736048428,15.1490102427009,577.906055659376));
#460=CARTESIAN_POINT('',(857.78736048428,15.4717289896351,574.769949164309));
#461=CARTESIAN_POINT('',(857.78736048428,15.1488258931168,571.633844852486));
#462=CARTESIAN_POINT('',(857.787360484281,14.2436927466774,568.748668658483));
#463=CARTESIAN_POINT('',(857.78736048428,12.812666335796,566.126103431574));
#464=CARTESIAN_POINT('',(857.78736048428,9.06420390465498,561.557431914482));
#465=CARTESIAN_POINT('',(857.78736048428,4.02853506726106,559.405824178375));
#466=CARTESIAN_POINT('',(857.78736048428,-3.20210603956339E-09,559.405824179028));
#467=CARTESIAN_POINT('',(857.891721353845,-4.11896094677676E-09,559.510185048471));
#468=CARTESIAN_POINT('',(857.891721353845,-4.00118627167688,559.510185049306));
#469=CARTESIAN_POINT('',(857.891721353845,-9.00266910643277,561.647250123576));
#470=CARTESIAN_POINT('',(857.891721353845,-12.7256041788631,566.184762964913));
#471=CARTESIAN_POINT('',(857.891721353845,-14.1469196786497,568.78945890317));
#472=CARTESIAN_POINT('',(857.891721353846,-15.045920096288,571.655023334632));
#473=CARTESIAN_POINT('',(857.891721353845,-15.3666408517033,574.769949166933));
#474=CARTESIAN_POINT('',(857.891721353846,-15.0461033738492,577.88487717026));
#475=CARTESIAN_POINT('',(857.891721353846,-14.1461865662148,580.750435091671));
#476=CARTESIAN_POINT('',(857.891721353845,-12.7283533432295,583.355154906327));
#477=CARTESIAN_POINT('',(857.891721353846,-10.8538730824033,585.623822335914));
#478=CARTESIAN_POINT('',(857.891721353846,-8.58520529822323,587.498303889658));
#479=CARTESIAN_POINT('',(857.891721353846,-5.98048560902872,588.916132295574));
#480=CARTESIAN_POINT('',(857.891721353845,-3.11492754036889,589.816067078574));
#481=CARTESIAN_POINT('',(857.891721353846,1.62414735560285E-10,590.136537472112));
#482=CARTESIAN_POINT('',(857.891721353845,3.1149275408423,589.816067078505));
#483=CARTESIAN_POINT('',(857.891721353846,5.98048560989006,588.916132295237));
#484=CARTESIAN_POINT('',(857.891721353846,8.58520529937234,587.498303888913));
#485=CARTESIAN_POINT('',(857.891721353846,10.8538730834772,585.623822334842));
#486=CARTESIAN_POINT('',(857.891721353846,12.7283533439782,583.355154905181));
#487=CARTESIAN_POINT('',(857.891721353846,14.146186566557,580.750435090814));
#488=CARTESIAN_POINT('',(857.891721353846,15.0461033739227,577.884877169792));
#489=CARTESIAN_POINT('',(857.891721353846,15.3666408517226,574.769949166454));
#490=CARTESIAN_POINT('',(857.891721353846,15.0459200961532,571.655023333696));
#491=CARTESIAN_POINT('',(857.891721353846,14.1469196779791,568.789458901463));
#492=CARTESIAN_POINT('',(857.891721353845,12.7256041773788,566.184762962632));
#493=CARTESIAN_POINT('',(857.891721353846,9.00266910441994,561.647250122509));
#494=CARTESIAN_POINT('',(857.891721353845,4.00118626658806,559.510185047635));
#495=CARTESIAN_POINT('',(857.891721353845,-4.11896094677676E-09,559.510185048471));
#496=CARTESIAN_POINT('',(857.907296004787,-5.03581594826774E-09,559.656949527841));
#497=CARTESIAN_POINT('',(857.907296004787,-3.96276148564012,559.656949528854));
#498=CARTESIAN_POINT('',(857.907296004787,-8.9162133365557,561.773737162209));
#499=CARTESIAN_POINT('',(857.907296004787,-12.6030897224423,566.267126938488));
#500=CARTESIAN_POINT('',(857.907296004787,-14.0107711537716,568.846558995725));
#501=CARTESIAN_POINT('',(857.907296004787,-14.9011841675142,571.68450880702));
#502=CARTESIAN_POINT('',(857.907296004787,-15.2188623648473,574.769949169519));
#503=CARTESIAN_POINT('',(857.907296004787,-14.9013663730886,577.855391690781));
#504=CARTESIAN_POINT('',(857.907296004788,-14.0100423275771,580.693335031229));
#505=CARTESIAN_POINT('',(857.907296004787,-12.6058228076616,583.272790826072));
#506=CARTESIAN_POINT('',(857.907296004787,-10.7494479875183,585.519397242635));
#507=CARTESIAN_POINT('',(857.907296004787,-8.50284121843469,587.375773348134));
#508=CARTESIAN_POINT('',(857.907296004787,-5.923385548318,588.779988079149));
#509=CARTESIAN_POINT('',(857.907296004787,-3.08544206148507,589.671329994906));
#510=CARTESIAN_POINT('',(857.907296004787,3.41831533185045E-10,589.988759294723));
#511=CARTESIAN_POINT('',(857.907296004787,3.08544206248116,589.671329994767));
#512=CARTESIAN_POINT('',(857.907296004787,5.92338555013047,588.779988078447));
#513=CARTESIAN_POINT('',(857.907296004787,8.50284122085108,587.375773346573));
#514=CARTESIAN_POINT('',(857.907296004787,10.7494479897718,585.519397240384));
#515=CARTESIAN_POINT('',(857.907296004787,12.605822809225,583.272790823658));
#516=CARTESIAN_POINT('',(857.907296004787,14.0100423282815,580.693335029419));
#517=CARTESIAN_POINT('',(857.907296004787,14.9013663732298,577.855391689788));
#518=CARTESIAN_POINT('',(857.907296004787,15.2188623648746,574.769949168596));
#519=CARTESIAN_POINT('',(857.907296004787,14.9011841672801,571.684508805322));
#520=CARTESIAN_POINT('',(857.907296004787,14.0107711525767,568.846558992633));
#521=CARTESIAN_POINT('',(857.907296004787,12.6030897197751,566.267126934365));
#522=CARTESIAN_POINT('',(857.907296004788,8.91621333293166,561.773737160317));
#523=CARTESIAN_POINT('',(857.907296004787,3.96276147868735,559.656949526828));
#524=CARTESIAN_POINT('',(857.907296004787,-5.03581594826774E-09,559.656949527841));
#525=CARTESIAN_POINT('',(857.907558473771,-5.0512666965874E-09,559.659422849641));
#526=CARTESIAN_POINT('',(857.907558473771,-3.96211393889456,559.659422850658));
#527=CARTESIAN_POINT('',(857.907558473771,-8.91475635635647,561.775868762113));
#528=CARTESIAN_POINT('',(857.907558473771,-12.6010250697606,566.268514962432));
#529=CARTESIAN_POINT('',(857.907558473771,-14.0084767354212,568.84752126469));
#530=CARTESIAN_POINT('',(857.907558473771,-14.8987450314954,571.685005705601));
#531=CARTESIAN_POINT('',(857.907558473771,-15.2163719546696,574.769949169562));
#532=CARTESIAN_POINT('',(857.907558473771,-14.8989272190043,577.85489479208));
#533=CARTESIAN_POINT('',(857.907558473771,-14.0077479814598,580.692372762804));
#534=CARTESIAN_POINT('',(857.907558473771,-12.603757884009,583.271402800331));
#535=CARTESIAN_POINT('',(857.907558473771,-10.7476881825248,585.517637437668));
#536=CARTESIAN_POINT('',(857.907558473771,-8.5014531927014,587.373708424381));
#537=CARTESIAN_POINT('',(857.907558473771,-5.92242327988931,588.777693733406));
#538=CARTESIAN_POINT('',(857.907558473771,-3.08494516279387,589.668890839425));
#539=CARTESIAN_POINT('',(857.907558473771,3.4485512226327E-10,589.986268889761));
#540=CARTESIAN_POINT('',(857.907558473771,3.08494516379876,589.668890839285));
#541=CARTESIAN_POINT('',(857.907558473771,5.92242328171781,588.777693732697));
#542=CARTESIAN_POINT('',(857.907558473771,8.50145319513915,587.373708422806));
#543=CARTESIAN_POINT('',(857.90755847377,10.7476881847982,585.517637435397));
#544=CARTESIAN_POINT('',(857.907558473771,12.6037578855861,583.271402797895));
#545=CARTESIAN_POINT('',(857.907558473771,14.0077479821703,580.692372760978));
#546=CARTESIAN_POINT('',(857.907558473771,14.8989272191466,577.854894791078));
#547=CARTESIAN_POINT('',(857.90755847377,15.216371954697,574.769949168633));
#548=CARTESIAN_POINT('',(857.907558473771,14.8987450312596,571.685005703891));
#549=CARTESIAN_POINT('',(857.90755847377,14.0084767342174,568.847521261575));
#550=CARTESIAN_POINT('',(857.907558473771,12.6010250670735,566.268514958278));
#551=CARTESIAN_POINT('',(857.907558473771,8.91475635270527,561.775868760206));
#552=CARTESIAN_POINT('',(857.907558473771,3.96211393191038,559.659422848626));
#553=CARTESIAN_POINT('',(857.907558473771,-5.0512666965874E-09,559.659422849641));
#554=CARTESIAN_POINT('',(857.907820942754,-5.06671874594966E-09,559.661896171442));
#555=CARTESIAN_POINT('',(857.907820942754,-3.96146639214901,559.661896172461));
#556=CARTESIAN_POINT('',(857.907820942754,-8.91329937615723,561.778000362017));
#557=CARTESIAN_POINT('',(857.907820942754,-12.5989604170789,566.269902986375));
#558=CARTESIAN_POINT('',(857.907820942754,-14.0061823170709,568.848483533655));
#559=CARTESIAN_POINT('',(857.907820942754,-14.8963058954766,571.685502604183));
#560=CARTESIAN_POINT('',(857.907820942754,-15.2138815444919,574.769949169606));
#561=CARTESIAN_POINT('',(857.907820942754,-14.8964880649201,577.854397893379));
#562=CARTESIAN_POINT('',(857.907820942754,-14.0054536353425,580.69141049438));
#563=CARTESIAN_POINT('',(857.907820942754,-12.6016929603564,583.27001477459));
#564=CARTESIAN_POINT('',(857.907820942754,-10.7459283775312,585.515877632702));
#565=CARTESIAN_POINT('',(857.907820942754,-8.50006516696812,587.371643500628));
#566=CARTESIAN_POINT('',(857.907820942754,-5.92146101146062,588.775399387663));
#567=CARTESIAN_POINT('',(857.907820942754,-3.08444826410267,589.666451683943));
#568=CARTESIAN_POINT('',(857.907820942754,3.47878711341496E-10,589.983778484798));
#569=CARTESIAN_POINT('',(857.907820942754,3.08444826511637,589.666451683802));
#570=CARTESIAN_POINT('',(857.907820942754,5.92146101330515,588.775399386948));
#571=CARTESIAN_POINT('',(857.907820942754,8.50006516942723,587.371643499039));
#572=CARTESIAN_POINT('',(857.907820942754,10.7459283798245,585.515877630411));
#573=CARTESIAN_POINT('',(857.907820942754,12.6016929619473,583.270014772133));
#574=CARTESIAN_POINT('',(857.907820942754,14.0054536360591,580.691410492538));
#575=CARTESIAN_POINT('',(857.907820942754,14.8964880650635,577.854397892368));
#576=CARTESIAN_POINT('',(857.907820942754,15.2138815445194,574.769949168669));
#577=CARTESIAN_POINT('',(857.907820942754,14.8963058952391,571.68550260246));
#578=CARTESIAN_POINT('',(857.907820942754,14.0061823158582,568.848483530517));
#579=CARTESIAN_POINT('',(857.907820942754,12.5989604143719,566.26990298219));
#580=CARTESIAN_POINT('',(857.907820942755,8.91329937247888,561.778000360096));
#581=CARTESIAN_POINT('',(857.907820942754,3.96146638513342,559.661896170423));
#582=CARTESIAN_POINT('',(857.907820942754,-5.06671874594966E-09,559.661896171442));
#583=CARTESIAN_POINT('',(857.908083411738,-5.08216949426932E-09,559.664369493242));
#584=CARTESIAN_POINT('',(857.908083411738,-3.96081884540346,559.664369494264));
#585=CARTESIAN_POINT('',(857.908083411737,-8.91184239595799,561.780131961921));
#586=CARTESIAN_POINT('',(857.908083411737,-12.5968957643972,566.271291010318));
#587=CARTESIAN_POINT('',(857.908083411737,-14.0038878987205,568.84944580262));
#588=CARTESIAN_POINT('',(857.908083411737,-14.8938667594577,571.685999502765));
#589=CARTESIAN_POINT('',(857.908083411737,-15.2113911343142,574.76994916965));
#590=CARTESIAN_POINT('',(857.908083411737,-14.8940489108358,577.853900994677));
#591=CARTESIAN_POINT('',(857.908083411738,-14.0031592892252,580.690448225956));
#592=CARTESIAN_POINT('',(857.908083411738,-12.5996280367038,583.268626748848));
#593=CARTESIAN_POINT('',(857.908083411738,-10.7441685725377,585.514117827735));
#594=CARTESIAN_POINT('',(857.908083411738,-8.49867714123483,587.369578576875));
#595=CARTESIAN_POINT('',(857.908083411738,-5.92049874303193,588.77310504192));
#596=CARTESIAN_POINT('',(857.908083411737,-3.08395136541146,589.664012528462));
#597=CARTESIAN_POINT('',(857.908083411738,3.50902300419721E-10,589.981288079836));
#598=CARTESIAN_POINT('',(857.908083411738,3.08395136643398,589.66401252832));
#599=CARTESIAN_POINT('',(857.908083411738,5.92049874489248,588.773105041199));
#600=CARTESIAN_POINT('',(857.908083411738,8.4986771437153,587.369578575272));
#601=CARTESIAN_POINT('',(857.908083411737,10.7441685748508,585.514117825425));
#602=CARTESIAN_POINT('',(857.908083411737,12.5996280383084,583.26862674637));
#603=CARTESIAN_POINT('',(857.908083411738,14.0031592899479,580.690448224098));
#604=CARTESIAN_POINT('',(857.908083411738,14.8940489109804,577.853900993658));
#605=CARTESIAN_POINT('',(857.908083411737,15.2113911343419,574.769949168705));
#606=CARTESIAN_POINT('',(857.908083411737,14.8938667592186,571.685999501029));
#607=CARTESIAN_POINT('',(857.908083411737,14.003887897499,568.849445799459));
#608=CARTESIAN_POINT('',(857.908083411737,12.5968957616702,566.271291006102));
#609=CARTESIAN_POINT('',(857.908083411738,8.91184239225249,561.780131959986));
#610=CARTESIAN_POINT('',(857.908083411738,3.96081883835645,559.66436949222));
#611=CARTESIAN_POINT('',(857.908083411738,-5.08216949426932E-09,559.664369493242));
#612=(BOUNDED_SURFACE() B_SPLINE_SURFACE(3,3,((#409,#410,#411,#412,#413,#414,#415,#416,#417,
#418,#419,#420,#421,#422,#423,#424,#425,#426,#427,#428,#429,#430,#431,#432,#433,#434,#435,#436,
#437),(#438,#439,#440,#441,#442,#443,#444,#445,#446,#447,#448,#449,#450,#451,#452,#453,#454,
#455,#456,#457,#458,#459,#460,#461,#462,#463,#464,#465,#466),(#467,#468,#469,#470,#471,#472,
#473,#474,#475,#476,#477,#478,#479,#480,#481,#482,#483,#484,#485,#486,#487,#488,#489,#490,#491,
#492,#493,#494,#495),(#496,#497,#498,#499,#500,#501,#502,#503,#504,#505,#506,#507,#508,#509,
#510,#511,#512,#513,#514,#515,#516,#517,#518,#519,#520,#521,#522,#523,#524),(#525,#526,#527,
#528,#529,#530,#531,#532,#533,#534,#535,#536,#537,#538,#539,#540,#541,#542,#543,#544,#545,#546,
#547,#548,#549,#550,#551,#552,#553),(#554,#555,#556,#557,#558,#559,#560,#561,#562,#563,#564,
#565,#566,#567,#568,#569,#570,#571,#572,#573,#574,#575,#576,#577,#578,#579,#580,#581,#582),
(#583,#584,#585,#586,#587,#588,#589,#590,#591,#592,#593,#594,#595,#596,#597,#598,#599,#600,#601,
#602,#603,#604,#605,#606,#607,#608,#609,#610,#611)),.UNSPECIFIED.,.F.,.T.,
.F.) B_SPLINE_SURFACE_WITH_KNOTS((4,3,4),(4,1,1,1,1,1,1,1,1,1,1,1,1,1,1,1,1,1,1,1,1,1,1,1,1,1,
4),(0.,1.,1.01978315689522),(0.,0.124999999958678,0.156249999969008,0.187499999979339,
0.218749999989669,0.25,0.28125,0.3125,0.34375,0.375,0.40625,0.4375,0.46875,0.5,
0.531249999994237,0.562499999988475,0.593749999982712,0.624999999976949,0.656249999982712,
0.687499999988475,0.718749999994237,0.75,0.781249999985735,0.812499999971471,0.843749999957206,
0.874999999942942,1.),
.UNSPECIFIED.) GEOMETRIC_REPRESENTATION_ITEM() RATIONAL_B_SPLINE_SURFACE(((1.,1.,1.,1.,1.,1.,1.,
1.,1.,1.,1.,1.,1.,1.,1.,1.,1.,1.,1.,1.,1.,1.,1.,1.,1.,1.,1.,1.,1.),(0.85185185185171,
0.85185185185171,0.85185185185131,0.851851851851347,0.851851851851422,0.851851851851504,
0.851851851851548,0.851851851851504,0.851851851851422,0.851851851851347,0.851851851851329,
0.851851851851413,0.851851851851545,0.851851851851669,0.851851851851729,0.851851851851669,
0.851851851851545,0.851851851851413,0.851851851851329,0.851851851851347,0.851851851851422,
0.851851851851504,0.851851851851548,0.851851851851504,0.851851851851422,0.851851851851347,
0.85185185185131,0.851851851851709,0.85185185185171),(0.85185185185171,0.85185185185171,
0.85185185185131,0.851851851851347,0.851851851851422,0.851851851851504,0.851851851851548,
0.851851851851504,0.851851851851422,0.851851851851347,0.851851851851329,0.851851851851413,
0.851851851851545,0.851851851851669,0.851851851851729,0.851851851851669,0.851851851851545,
0.851851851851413,0.851851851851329,0.851851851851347,0.851851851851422,0.851851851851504,
0.851851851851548,0.851851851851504,0.851851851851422,0.851851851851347,0.85185185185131,
0.851851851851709,0.85185185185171),(1.,1.,1.,1.,1.,1.,1.,1.,1.,1.,1.,1.,1.,1.,1.,1.,1.,1.,1.,
1.,1.,1.,1.,1.,1.,1.,1.,1.,1.),(1.,1.,1.,1.,1.,1.,1.,1.,1.,1.,1.,1.,1.,1.,1.,1.,1.,1.,1.,1.,1.,
1.,1.,1.,1.,1.,1.,1.,1.),(1.,1.,1.,1.,1.,1.,1.,1.,1.,1.,1.,1.,1.,1.,1.,1.,1.,1.,1.,1.,1.,1.,1.,
1.,1.,1.,1.,1.,1.),(1.,1.,1.,1.,1.,1.,1.,1.,1.,1.,1.,1.,1.,1.,1.,1.,1.,1.,1.,1.,1.,1.,1.,1.,1.,
1.,1.,1.,1.))) REPRESENTATION_ITEM('') SURFACE());
#613=CARTESIAN_POINT('',(857.640596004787,-2.28525098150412E-09,559.390249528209));
#614=CARTESIAN_POINT('',(857.64255621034,-2.29749660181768E-09,559.390457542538));
#615=CARTESIAN_POINT('',(857.644514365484,-2.30978491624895E-09,559.39068487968));
#616=CARTESIAN_POINT('',(857.648439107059,-2.33452901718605E-09,559.391179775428));
#617=CARTESIAN_POINT('',(857.650405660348,-2.34698537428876E-09,559.391447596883));
#618=CARTESIAN_POINT('',(857.65434606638,-2.37206389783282E-09,559.392024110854));
#619=CARTESIAN_POINT('',(857.656319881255,-2.38468661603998E-09,559.392333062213));
#620=CARTESIAN_POINT('',(857.660273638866,-2.41009591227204E-09,559.392992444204));
#621=CARTESIAN_POINT('',(857.662253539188,-2.42288302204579E-09,559.393343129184));
#622=CARTESIAN_POINT('',(857.666218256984,-2.44861888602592E-09,559.394086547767));
#623=CARTESIAN_POINT('',(857.668203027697,-2.46156815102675E-09,559.394479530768));
#624=CARTESIAN_POINT('',(857.67217623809,-2.48762583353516E-09,559.395308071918));
#625=CARTESIAN_POINT('',(857.674164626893,-2.50073473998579E-09,559.395743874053));
#626=CARTESIAN_POINT('',(857.678143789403,-2.52710893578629E-09,559.396658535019));
#627=CARTESIAN_POINT('',(857.680134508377,-2.54037469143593E-09,559.397137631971));
#628=CARTESIAN_POINT('',(857.684117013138,-2.56705953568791E-09,559.398139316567));
#629=CARTESIAN_POINT('',(857.686108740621,-2.58047906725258E-09,559.398662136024));
#630=CARTESIAN_POINT('',(857.690091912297,-2.60746813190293E-09,559.399751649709));
#631=CARTESIAN_POINT('',(857.692083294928,-2.62103808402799E-09,559.400318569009));
#632=CARTESIAN_POINT('',(857.696064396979,-2.64832437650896E-09,559.401496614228));
#633=CARTESIAN_POINT('',(857.698054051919,-2.66204111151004E-09,559.402107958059));
#634=CARTESIAN_POINT('',(857.702030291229,-2.68961707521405E-09,559.403375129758));
#635=CARTESIAN_POINT('',(857.704016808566,-2.70347667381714E-09,559.404031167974));
#636=CARTESIAN_POINT('',(857.707985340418,-2.73133419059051E-09,559.405387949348));
#637=CARTESIAN_POINT('',(857.709967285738,-2.74533245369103E-09,559.406088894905));
#638=CARTESIAN_POINT('',(857.713925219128,-2.77346284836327E-09,559.407535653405));
#639=CARTESIAN_POINT('',(857.715901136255,-2.78759529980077E-09,559.408281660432));
#640=CARTESIAN_POINT('',(857.719845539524,-2.81598934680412E-09,559.409818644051));
#641=CARTESIAN_POINT('',(857.721813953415,-2.83025123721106E-09,559.410609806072));
#642=CARTESIAN_POINT('',(857.725741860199,-2.85889916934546E-09,559.412237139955));
#643=CARTESIAN_POINT('',(857.727701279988,-2.87328548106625E-09,559.413073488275));
#644=CARTESIAN_POINT('',(857.731609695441,-2.90217700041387E-09,559.414791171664));
#645=CARTESIAN_POINT('',(857.733558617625,-2.91668245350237E-09,559.415672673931));
#646=CARTESIAN_POINT('',(857.737444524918,-2.94580674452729E-09,559.417480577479));
#647=CARTESIAN_POINT('',(857.739381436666,-2.96042580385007E-09,559.41840713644));
#648=CARTESIAN_POINT('',(857.74324180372,-2.98977154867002E-09,559.420304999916));
#649=CARTESIAN_POINT('',(857.745165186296,-3.00449843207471E-09,559.421276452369));
#650=CARTESIAN_POINT('',(857.748996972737,-3.03405382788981E-09,559.423263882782));
#651=CARTESIAN_POINT('',(857.750905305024,-3.04888251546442E-09,559.424279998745));
#652=CARTESIAN_POINT('',(857.754705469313,-3.0786352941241E-09,559.426356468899));
#653=CARTESIAN_POINT('',(857.756597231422,-3.09355953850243E-09,559.427416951));
#654=CARTESIAN_POINT('',(857.760362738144,-3.12349698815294E-09,559.429581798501));
#655=CARTESIAN_POINT('',(857.762236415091,-3.13851032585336E-09,559.430686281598));
#656=CARTESIAN_POINT('',(857.765964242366,-3.16861931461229E-09,559.432938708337));
#657=CARTESIAN_POINT('',(857.767818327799,-3.18371507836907E-09,559.43408675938));
#658=CARTESIAN_POINT('',(857.771505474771,-3.21398207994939E-09,559.436425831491));
#659=CARTESIAN_POINT('',(857.773338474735,-3.22915341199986E-09,559.437616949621));
#660=CARTESIAN_POINT('',(857.776981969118,-3.25956453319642E-09,559.440041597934));
#661=CARTESIAN_POINT('',(857.778792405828,-3.27480439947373E-09,559.441275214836));
#662=CARTESIAN_POINT('',(857.782389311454,-3.30534540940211E-09,559.443784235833));
#663=CARTESIAN_POINT('',(857.784175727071,-3.32064661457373E-09,559.445059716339));
#664=CARTESIAN_POINT('',(857.787723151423,-3.35130297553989E-09,559.447651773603));
#665=CARTESIAN_POINT('',(857.789484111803,-3.36665817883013E-09,559.448968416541));
#666=CARTESIAN_POINT('',(857.792979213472,-3.39741507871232E-09,559.451642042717));
#667=CARTESIAN_POINT('',(857.794713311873,-3.41281681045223E-09,559.45299908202));
#668=CARTESIAN_POINT('',(857.798153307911,-3.44365919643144E-09,559.455752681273));
#669=CARTESIAN_POINT('',(857.79985916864,-3.45909987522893E-09,559.45714928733));
#670=CARTESIAN_POINT('',(857.803241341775,-3.49001248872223E-09,559.459981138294));
#671=CARTESIAN_POINT('',(857.80491762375,-3.50548443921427E-09,559.461416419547));
#672=CARTESIAN_POINT('',(857.808239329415,-3.53645185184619E-09,559.464324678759));
#673=CARTESIAN_POINT('',(857.809884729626,-3.55194732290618E-09,559.465797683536));
#674=CARTESIAN_POINT('',(857.813143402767,-3.58295397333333E-09,559.468780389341));
#675=CARTESIAN_POINT('',(857.814756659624,-3.59846515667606E-09,559.470290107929));
#676=CARTESIAN_POINT('',(857.817949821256,-3.62949538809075E-09,559.473345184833));
#677=CARTESIAN_POINT('',(857.819529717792,-3.64501443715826E-09,559.474890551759));
#678=CARTESIAN_POINT('',(857.822654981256,-3.67605253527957E-09,559.478015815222));
#679=CARTESIAN_POINT('',(857.824200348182,-3.69157158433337E-09,559.479595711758));
#680=CARTESIAN_POINT('',(857.827255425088,-3.72260181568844E-09,559.482788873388));
#681=CARTESIAN_POINT('',(857.828765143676,-3.73811299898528E-09,559.484402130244));
#682=CARTESIAN_POINT('',(857.831747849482,-3.76911964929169E-09,559.487660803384));
#683=CARTESIAN_POINT('',(857.833220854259,-3.78461512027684E-09,559.489306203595));
#684=CARTESIAN_POINT('',(857.836129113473,-3.81558253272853E-09,559.492627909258));
#685=CARTESIAN_POINT('',(857.837564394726,-3.8310544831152E-09,559.494304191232));
#686=CARTESIAN_POINT('',(857.84039624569,-3.86196709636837E-09,559.497686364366));
#687=CARTESIAN_POINT('',(857.841792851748,-3.87740777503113E-09,559.499392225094));
#688=CARTESIAN_POINT('',(857.844546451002,-3.90825016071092E-09,559.50283222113));
#689=CARTESIAN_POINT('',(857.845903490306,-3.92365189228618E-09,559.50456631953));
#690=CARTESIAN_POINT('',(857.848577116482,-3.95440879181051E-09,559.508061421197));
#691=CARTESIAN_POINT('',(857.849893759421,-3.96976399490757E-09,559.509822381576));
#692=CARTESIAN_POINT('',(857.852485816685,-4.00042035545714E-09,559.513369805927));
#693=CARTESIAN_POINT('',(857.853761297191,-4.0157215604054E-09,559.515156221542));
#694=CARTESIAN_POINT('',(857.856270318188,-4.04626256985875E-09,559.518753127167));
#695=CARTESIAN_POINT('',(857.85750393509,-4.06150243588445E-09,559.520563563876));
#696=CARTESIAN_POINT('',(857.859928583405,-4.09191355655E-09,559.524207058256));
#697=CARTESIAN_POINT('',(857.861119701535,-4.10708488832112E-09,559.526040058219));
#698=CARTESIAN_POINT('',(857.863458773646,-4.1373518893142E-09,559.529727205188));
#699=CARTESIAN_POINT('',(857.864606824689,-4.15244765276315E-09,559.531581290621));
#700=CARTESIAN_POINT('',(857.866859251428,-4.18255664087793E-09,559.535309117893));
#701=CARTESIAN_POINT('',(857.867963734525,-4.19756997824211E-09,559.537182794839));
#702=CARTESIAN_POINT('',(857.870128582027,-4.22750742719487E-09,559.540948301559));
#703=CARTESIAN_POINT('',(857.871189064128,-4.24243167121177E-09,559.542840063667));
#704=CARTESIAN_POINT('',(857.873265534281,-4.27218444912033E-09,559.546640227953));
#705=CARTESIAN_POINT('',(857.874281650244,-4.28701313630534E-09,559.548548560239));
#706=CARTESIAN_POINT('',(857.876269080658,-4.31656853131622E-09,559.552380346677));
#707=CARTESIAN_POINT('',(857.877240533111,-4.3312954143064E-09,559.554303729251));
#708=CARTESIAN_POINT('',(857.879138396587,-4.3606411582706E-09,559.558164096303));
#709=CARTESIAN_POINT('',(857.880064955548,-4.37526021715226E-09,559.56010100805));
#710=CARTESIAN_POINT('',(857.881872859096,-4.40438450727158E-09,559.563986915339));
#711=CARTESIAN_POINT('',(857.882754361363,-4.41888995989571E-09,559.565935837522));
#712=CARTESIAN_POINT('',(857.884472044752,-4.44778147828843E-09,559.569844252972));
#713=CARTESIAN_POINT('',(857.885308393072,-4.46216778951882E-09,559.57180367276));
#714=CARTESIAN_POINT('',(857.886935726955,-4.49081572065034E-09,559.575731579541));
#715=CARTESIAN_POINT('',(857.887726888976,-4.50507761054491E-09,559.57769999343));
#716=CARTESIAN_POINT('',(857.889263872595,-4.53347165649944E-09,559.581644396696));
#717=CARTESIAN_POINT('',(857.890009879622,-4.5476041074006E-09,559.583620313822));
#718=CARTESIAN_POINT('',(857.891456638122,-4.57573450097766E-09,559.587578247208));
#719=CARTESIAN_POINT('',(857.892157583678,-4.58973276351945E-09,559.589560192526));
#720=CARTESIAN_POINT('',(857.893514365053,-4.61759027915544E-09,559.593528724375));
#721=CARTESIAN_POINT('',(857.894170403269,-4.63144987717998E-09,559.59551524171));
#722=CARTESIAN_POINT('',(857.895437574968,-4.65902583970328E-09,559.599491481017));
#723=CARTESIAN_POINT('',(857.896048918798,-4.67274257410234E-09,559.601481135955));
#724=CARTESIAN_POINT('',(857.897226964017,-4.7000288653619E-09,559.605462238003));
#725=CARTESIAN_POINT('',(857.897793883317,-4.71359881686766E-09,559.607453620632));
#726=CARTESIAN_POINT('',(857.898883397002,-4.74058788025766E-09,559.611436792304));
#727=CARTESIAN_POINT('',(857.899406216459,-4.75400741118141E-09,559.613428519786));
#728=CARTESIAN_POINT('',(857.900407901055,-4.78069225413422E-09,559.617411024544));
#729=CARTESIAN_POINT('',(857.900886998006,-4.79395800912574E-09,559.619401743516));
#730=CARTESIAN_POINT('',(857.901801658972,-4.82033220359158E-09,559.623380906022));
#731=CARTESIAN_POINT('',(857.902237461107,-4.83344110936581E-09,559.625369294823));
#732=CARTESIAN_POINT('',(857.903066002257,-4.85949879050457E-09,559.629342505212));
#733=CARTESIAN_POINT('',(857.903458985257,-4.87244805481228E-09,559.631327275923));
#734=CARTESIAN_POINT('',(857.904202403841,-4.89818391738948E-09,559.635291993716));
#735=CARTESIAN_POINT('',(857.904553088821,-4.91097102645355E-09,559.637271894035));
#736=CARTESIAN_POINT('',(857.905212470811,-4.93638032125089E-09,559.641225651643));
#737=CARTESIAN_POINT('',(857.90552142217,-4.94900303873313E-09,559.643199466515));
#738=CARTESIAN_POINT('',(857.90609793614,-4.97408156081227E-09,559.647139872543));
#739=CARTESIAN_POINT('',(857.906365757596,-4.9865379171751E-09,559.64910642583));
#740=CARTESIAN_POINT('',(857.906860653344,-5.01128201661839E-09,559.653031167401));
#741=CARTESIAN_POINT('',(857.907087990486,-5.02357033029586E-09,559.654989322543));
#742=CARTESIAN_POINT('',(857.907296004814,-5.03581594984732E-09,559.656949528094));
#743=B_SPLINE_CURVE_WITH_KNOTS('',3,(#613,#614,#615,#616,#617,#618,#619,#620,#621,#622,#623,
#624,#625,#626,#627,#628,#629,#630,#631,#632,#633,#634,#635,#636,#637,#638,#639,#640,#641,#642,
#643,#644,#645,#646,#647,#648,#649,#650,#651,#652,#653,#654,#655,#656,#657,#658,#659,#660,#661,
#662,#663,#664,#665,#666,#667,#668,#669,#670,#671,#672,#673,#674,#675,#676,#677,#678,#679,#680,
#681,#682,#683,#684,#685,#686,#687,#688,#689,#690,#691,#692,#693,#694,#695,#696,#697,#698,#699,
#700,#701,#702,#703,#704,#705,#706,#707,#708,#709,#710,#711,#712,#713,#714,#715,#716,#717,#718,
#719,#720,#721,#722,#723,#724,#725,#726,#727,#728,#729,#730,#731,#732,#733,#734,#735,#736,#737,
#738,#739,#740,#741,#742),.UNSPECIFIED.,.F.,.F.,(4,2,2,2,2,2,2,2,2,2,2,2,2,2,2,2,2,2,2,2,2,2,2,
2,2,2,2,2,2,2,2,2,2,2,2,2,2,2,2,2,2,2,2,2,2,2,2,2,2,2,2,2,2,2,2,2,2,2,2,2,2,2,2,2,4),(0.,
0.00591354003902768,0.0118672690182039,0.0178604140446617,0.0238921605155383,0.0299616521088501,
0.0360679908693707,0.0422102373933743,0.0483874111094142,0.0545984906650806,0.0608424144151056,
0.0671180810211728,0.0734243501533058,0.0797600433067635,0.086123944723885,0.0925148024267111,
0.0989313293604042,0.105372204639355,0.111836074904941,0.118321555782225,0.124827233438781,
0.131351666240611,0.137893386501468,0.14445090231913,0.151022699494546,0.157607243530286,
0.164202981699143,0.170808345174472,0.177421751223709,0.184041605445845,0.190666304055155,
0.197294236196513,0.203923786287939,0.210553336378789,0.217181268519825,0.223805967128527,
0.230425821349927,0.237039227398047,0.243644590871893,0.250240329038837,0.256824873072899,
0.263396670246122,0.269954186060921,0.276495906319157,0.283020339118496,0.289526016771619,
0.29601149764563,0.302475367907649,0.308916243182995,0.31533277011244,0.321723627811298,
0.328087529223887,0.334423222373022,0.34072949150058,0.347005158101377,0.353249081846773,
0.359460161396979,0.365637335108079,0.371779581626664,0.377885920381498,0.38395541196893,
0.389987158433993,0.395980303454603,0.401934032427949,0.407847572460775),.UNSPECIFIED.);
#744=EDGE_CURVE('BSEAM74',#400,#180,#743,.T.);
#745=ORIENTED_EDGE('',*,*,#401,.T.);
#746=ORIENTED_EDGE('',*,*,#181,.T.);
#747=ORIENTED_EDGE('',*,*,#744,.T.);
#748=ORIENTED_EDGE('',*,*,#744,.F.);
#749=EDGE_LOOP('',(#745,#747,#746,#748));
#750=FACE_BOUND('',#749,.T.);
#751=ADVANCED_FACE('F74',(#750),#612,.T.);
#752=CLOSED_SHELL('',(#196,#408,#751));
#753=MANIFOLD_SOLID_BREP('B2',#752);
#754=ADVANCED_BREP_SHAPE_REPRESENTATION('',(#18,#753),#14);
#755=SHAPE_DEFINITION_REPRESENTATION(#9,#754);
ENDSEC;
END-ISO-10303-21;
